VERSION 5.8 ;
BUSBITCHARS "[]" ;
DIVIDERCHAR "/" ;
UNITS
    DATABASE MICRONS 1000 ;
END UNITS

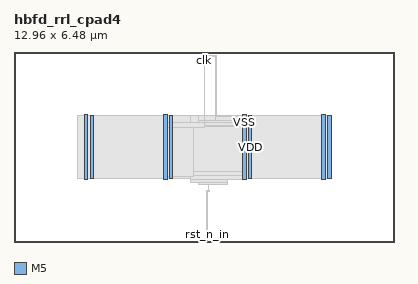
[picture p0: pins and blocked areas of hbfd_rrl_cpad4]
MACRO hbfd_rrl_cpad4
  FOREIGN hbfd_rrl_cpad4 0 0 ;
  CLASS BLOCK ;
  SIZE 12.96 BY 6.48 ;
  PIN clk
    DIRECTION INPUT ;
    USE SIGNAL ;
    PORT
      LAYER M5 ;
        RECT  6.48 6.396 6.504 6.48 ;
    END
  END clk
  PIN rst_n
    DIRECTION OUTPUT ;
    USE SIGNAL ;
    PORT
      LAYER M5 ;
        RECT  6.576 6.396 6.6 6.48 ;
    END
  END rst_n
  PIN rst_n_in
    DIRECTION INPUT ;
    USE SIGNAL ;
    PORT
      LAYER M5 ;
        RECT  6.576 0 6.6 0.084 ;
    END
  END rst_n_in
  PIN VDD
    DIRECTION INOUT ;
    USE POWER ;
    PORT
      LAYER M5 ;
        RECT  10.692 2.151 10.812 4.329 ;
        RECT  7.992 2.151 8.112 4.329 ;
        RECT  5.292 2.151 5.412 4.329 ;
        RECT  2.592 2.151 2.712 4.329 ;
    END
  END VDD
  PIN VSS
    DIRECTION INOUT ;
    USE GROUND ;
    PORT
      LAYER M5 ;
        RECT  10.5 2.137 10.62 4.343 ;
        RECT  7.8 2.137 7.92 4.343 ;
        RECT  5.1 2.137 5.22 4.343 ;
        RECT  2.4 2.137 2.52 4.343 ;
    END
  END VSS
  OBS
    LAYER RVTN ;
     RECT  2.16 2.16 10.8 2.295 ;
     RECT  2.16 2.565 10.8 2.835 ;
     RECT  2.16 3.105 10.8 3.375 ;
     RECT  2.16 3.645 10.8 3.915 ;
     RECT  2.16 4.185 10.8 4.32 ;
    LAYER RVTP ;
     RECT  2.16 2.295 10.8 2.565 ;
     RECT  2.16 2.835 10.8 3.105 ;
     RECT  2.16 3.375 10.8 3.645 ;
     RECT  2.16 3.915 10.8 4.185 ;
    LAYER M1 ;
     RECT  2.16 2.151 10.8 4.329 ;
    LAYER M2 ;
     RECT  2.16 2.151 6.007 4.329 ;
     RECT  6.007 2.034 6.295 4.329 ;
     RECT  6.295 1.962 7.295 4.329 ;
     RECT  7.295 2.151 10.8 4.329 ;
     RECT  10.8 2.421 10.812 4.059 ;
    LAYER M3 ;
     RECT  6.624 1.723 6.642 1.957 ;
     RECT  6.3 1.957 7.29 2.029 ;
     RECT  6.012 2.029 7.29 2.143 ;
     RECT  5.115 2.143 5.205 2.251 ;
     RECT  6.012 2.143 7.905 2.251 ;
     RECT  2.415 2.143 2.505 2.413 ;
     RECT  5.115 2.251 7.905 2.413 ;
     RECT  10.515 2.143 10.605 2.413 ;
     RECT  5.115 2.413 8.097 3.965 ;
     RECT  2.415 2.413 2.697 4.067 ;
     RECT  5.115 3.965 5.397 4.067 ;
     RECT  6.3 3.965 8.097 4.067 ;
     RECT  10.515 2.413 10.797 4.067 ;
     RECT  6.3 4.067 7.905 4.145 ;
     RECT  6.876 4.145 7.905 4.289 ;
     RECT  2.415 4.067 2.505 4.337 ;
     RECT  5.115 4.067 5.205 4.337 ;
     RECT  7.815 4.289 7.905 4.337 ;
     RECT  10.515 4.067 10.605 4.337 ;
     RECT  6.876 4.289 6.894 6.365 ;
    LAYER M4 ;
     RECT  2.408 2.148 2.512 4.332 ;
     RECT  2.512 2.418 2.704 4.062 ;
     RECT  5.108 2.148 5.212 4.332 ;
     RECT  5.212 2.256 5.404 4.062 ;
     RECT  5.404 2.256 6.131 2.28 ;
     RECT  5.404 3.552 6.131 4.056 ;
     RECT  6.131 3.936 6.329 4.056 ;
     RECT  6.565 1.728 6.653 1.752 ;
     RECT  6.565 6.336 6.905 6.36 ;
     RECT  6.329 3.936 7.808 3.96 ;
     RECT  7.808 2.148 7.912 4.332 ;
     RECT  7.912 2.418 8.104 4.062 ;
     RECT  10.508 2.148 10.612 4.332 ;
     RECT  10.612 2.418 10.804 4.062 ;
    LAYER M5 ;
     RECT  6.576 0.016 6.6 1.763 ;
     RECT  2.4 2.137 2.52 2.151 ;
     RECT  5.1 2.137 5.22 2.151 ;
     RECT  7.8 2.137 7.92 2.151 ;
     RECT  10.5 2.137 10.62 2.151 ;
     RECT  5.1 2.151 5.412 2.245 ;
     RECT  5.1 2.245 6.12 3.906 ;
     RECT  5.1 3.906 6.504 4.067 ;
     RECT  2.4 2.151 2.712 4.329 ;
     RECT  5.1 4.067 5.412 4.329 ;
     RECT  7.8 2.151 8.112 4.329 ;
     RECT  10.5 2.151 10.812 4.329 ;
     RECT  2.4 4.329 2.52 4.343 ;
     RECT  5.1 4.329 5.22 4.343 ;
     RECT  7.8 4.329 7.92 4.343 ;
     RECT  10.5 4.329 10.62 4.343 ;
     RECT  6.48 4.067 6.504 6.325 ;
     RECT  6.48 6.325 6.6 6.416 ;
  END
END hbfd_rrl_cpad4
END LIBRARY
